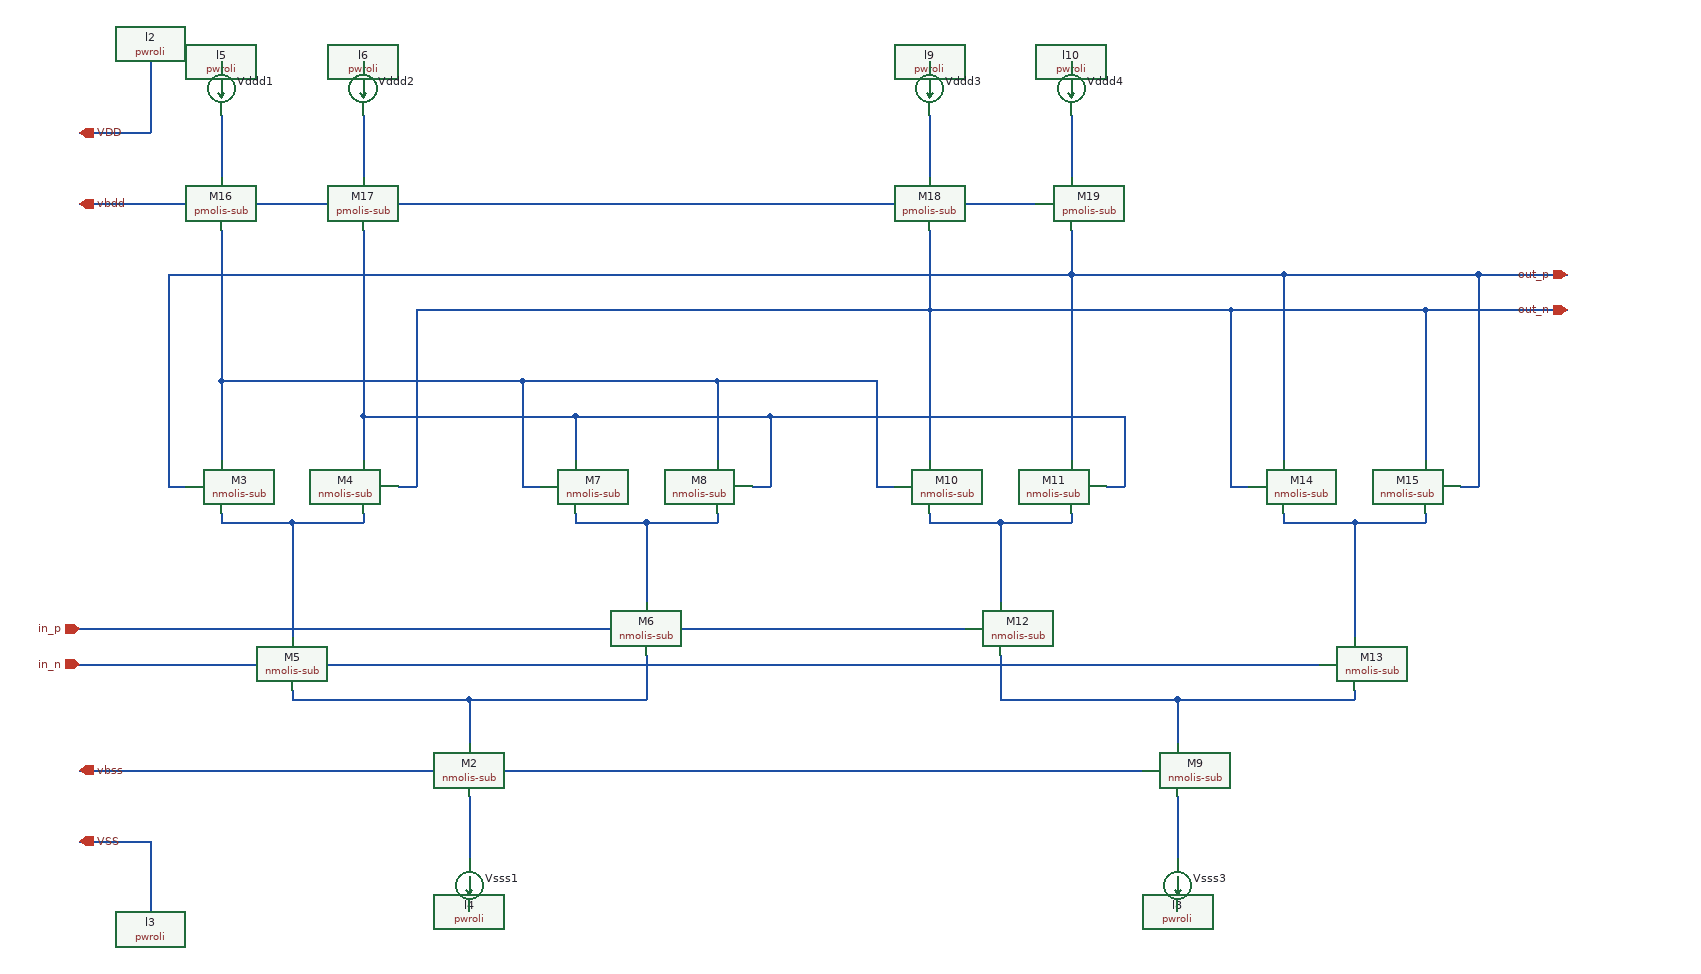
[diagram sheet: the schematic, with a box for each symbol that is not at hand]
v {xschem version=3.4.6 file_version=1.2
*
* This file is part of XSCHEM,
* a schematic capture and Spice/Vhdl/Verilog netlisting tool for circuit
* simulation.
* Copyright (C) 1998-2023 Stefan Frederik Schippers
*
* This program is free software; you can redistribute it and/or modify
* it under the terms of the GNU General Public License as published by
* the Free Software Foundation; either version 2 of the License, or
* (at your option) any later version.
*
* This program is distributed in the hope that it will be useful,
* but WITHOUT ANY WARRANTY; without even the implied warranty of
* MERCHANTABILITY or FITNESS FOR A PARTICULAR PURPOSE.  See the
* GNU General Public License for more details.
*
* You should have received a copy of the GNU General Public License
* along with this program; if not, write to the Free Software
* Foundation, Inc., 51 Franklin Street, Fifth Floor, Boston, MA 02110-1301 USA
}
G {}
K {}
V {}
S {}
E {}
N 1040 -600 1120 -600 {lab=#net1}
N 1040 -600 1040 -510 {lab=#net1}
N 960 -600 1040 -600 {lab=#net1}
N 960 -610 960 -600 {lab=#net1}
N 1120 -610 1120 -600 {lab=#net1}
N 640 -600 720 -600 {lab=#net2}
N 640 -600 640 -470 {lab=#net2}
N 560 -600 640 -600 {lab=#net2}
N 560 -610 560 -600 {lab=#net2}
N 720 -610 720 -600 {lab=#net2}
N 560 -760 560 -670 {lab=#net3}
N 720 -720 720 -670 {lab=#net4}
N 560 -930 560 -760 {lab=#net3}
N 1120 -760 1120 -670 {lab=#net3}
N 720 -720 960 -720 {lab=#net4}
N 720 -930 720 -720 {lab=#net4}
N 960 -720 960 -670 {lab=#net4}
N 900 -640 920 -640 {lab=#net3}
N 900 -760 900 -640 {lab=#net3}
N 560 -760 900 -760 {lab=#net3}
N 960 -720 1180 -720 {lab=#net4}
N 1180 -720 1180 -640 {lab=#net4}
N 1160 -640 1180 -640 {lab=#net4}
N 560 -1060 560 -990 {lab=#net5}
N 720 -1060 720 -990 {lab=#net6}
N 1840 -600 1920 -600 {lab=#net7}
N 1840 -600 1840 -470 {lab=#net7}
N 1760 -600 1840 -600 {lab=#net7}
N 1760 -610 1760 -600 {lab=#net7}
N 1920 -610 1920 -600 {lab=#net7}
N 1440 -600 1520 -600 {lab=#net8}
N 1440 -600 1440 -510 {lab=#net8}
N 1360 -600 1440 -600 {lab=#net8}
N 1360 -610 1360 -600 {lab=#net8}
N 1520 -610 1520 -600 {lab=#net8}
N 1360 -840 1360 -670 {lab=out_n}
N 1520 -880 1520 -670 {lab=out_p}
N 1700 -840 1920 -840 {lab=out_n}
N 1360 -930 1360 -840 {lab=out_n}
N 1920 -840 1920 -670 {lab=out_n}
N 1520 -930 1520 -880 {lab=out_p}
N 1760 -880 1760 -670 {lab=out_p}
N 1700 -640 1720 -640 {lab=out_n}
N 1700 -840 1700 -640 {lab=out_n}
N 1760 -880 1980 -880 {lab=out_p}
N 1980 -880 1980 -640 {lab=out_p}
N 1960 -640 1980 -640 {lab=out_p}
N 1360 -1060 1360 -990 {lab=#net9}
N 1520 -1060 1520 -990 {lab=#net10}
N 1560 -640 1580 -640 {lab=#net4}
N 900 -760 1120 -760 {lab=#net3}
N 500 -640 520 -640 {lab=out_p}
N 760 -640 780 -640 {lab=out_n}
N 1520 -880 1760 -880 {lab=out_p}
N 1180 -720 1580 -720 {lab=#net4}
N 1580 -720 1580 -640 {lab=#net4}
N 1120 -760 1300 -760 {lab=#net3}
N 1300 -760 1300 -640 {lab=#net3}
N 1300 -640 1320 -640 {lab=#net3}
N 500 -880 1520 -880 {lab=out_p}
N 500 -880 500 -640 {lab=out_p}
N 780 -840 780 -640 {lab=out_n}
N 1360 -840 1700 -840 {lab=out_n}
N 780 -840 1360 -840 {lab=out_n}
N 1980 -880 2080 -880 {lab=out_p}
N 1920 -840 2080 -840 {lab=out_n}
N 840 -400 1040 -400 {lab=#net11}
N 840 -400 840 -350 {lab=#net11}
N 640 -400 840 -400 {lab=#net11}
N 1640 -400 1840 -400 {lab=#net12}
N 1640 -400 1640 -350 {lab=#net12}
N 1440 -400 1640 -400 {lab=#net12}
N 840 -290 840 -220 {lab=#net13}
N 1640 -290 1640 -220 {lab=#net14}
N 640 -410 640 -400 {lab=#net11}
N 1040 -450 1040 -400 {lab=#net11}
N 1440 -450 1440 -400 {lab=#net12}
N 1840 -410 1840 -400 {lab=#net12}
N 400 -960 1480 -960 {lab=vbdd}
N 400 -320 1600 -320 {lab=vbss}
N 400 -480 1400 -480 {lab=in_p}
N 400 -440 1800 -440 {lab=in_n}
N 400 -1040 480 -1040 {
lab=VDD}
N 480 -1120 480 -1040 {
lab=VDD}
N 400 -240 480 -240 {
lab=VSS}
N 480 -240 480 -160 {
lab=VSS}
C {title.sym} 160 -30 0 0 {name=l1 author="om"  net_name=true}
C {pwroli.sym} 840 -160 0 0 {name=l4 lab=VSS}
C {ammeter.sym} 840 -190 0 0 {name=Vsss1 
savecurrent=true
lvs_ignore=short}
C {pwroli.sym} 560 -1120 2 0 {name=l5 lab=VDD
}
C {pwroli.sym} 720 -1120 2 0 {name=l6 lab=VDD
}
C {ammeter.sym} 560 -1090 0 0 {name=Vddd1
savecurrent=true
lvs_ignore=short}
C {ammeter.sym} 720 -1090 0 0 {name=Vddd2
savecurrent=true
lvs_ignore=short}
C {pwroli.sym} 1640 -160 0 0 {name=l8 lab=VSS}
C {ammeter.sym} 1640 -190 0 0 {name=Vsss3 
savecurrent=true
lvs_ignore=short}
C {pwroli.sym} 1360 -1120 2 0 {name=l9 lab=VDD
}
C {pwroli.sym} 1520 -1120 2 0 {name=l10 lab=VDD
}
C {ammeter.sym} 1360 -1090 0 0 {name=Vddd3
savecurrent=true
lvs_ignore=short}
C {ammeter.sym} 1520 -1090 0 0 {name=Vddd4
savecurrent=true
lvs_ignore=short}
C {ngspice_probe.sym} 1840 -400 0 0 {name=r7}
C {ngspice_probe.sym} 1040 -400 0 0 {name=r9}
C {ngspice_probe.sym} 680 -600 0 0 {name=r11}
C {ngspice_probe.sym} 1060 -600 0 0 {name=r12}
C {ngspice_probe.sym} 1470 -600 0 0 {name=r14}
C {ngspice_probe.sym} 1870 -600 0 0 {name=r15}
C {ngspice_probe.sym} 1860 -880 0 0 {name=r16}
C {ngspice_probe.sym} 1860 -840 0 0 {name=r17}
C {nmolis-sub.sym} 820 -320 0 0 {name=M2
l=0.13u
w=0.15u
ng=1
m=1
substrate=VSS
model=sg13_lv_nmos
spiceprefix=X
}
C {nmolis-sub.sym} 540 -640 0 0 {name=M3
l=0.13u
w=0.15u
ng=1
m=1
substrate=VSS
model=sg13_lv_nmos
spiceprefix=X
}
C {nmolis-sub.sym} 740 -640 0 1 {name=M4
l=0.13u
w=0.15u
ng=1
m=1
substrate=VSS
model=sg13_lv_nmos
spiceprefix=X
}
C {nmolis-sub.sym} 620 -440 0 0 {name=M5
l=0.13u
w=0.15u
ng=1
m=1
substrate=VSS
model=sg13_lv_nmos
spiceprefix=X
}
C {nmolis-sub.sym} 1020 -480 0 0 {name=M6
l=0.13u
w=0.15u
ng=1
m=1
substrate=VSS
model=sg13_lv_nmos
spiceprefix=X
}
C {nmolis-sub.sym} 940 -640 0 0 {name=M7
l=0.13u
w=0.15u
ng=1
m=1
substrate=VSS
model=sg13_lv_nmos
spiceprefix=X
}
C {nmolis-sub.sym} 1140 -640 0 1 {name=M8
l=0.13u
w=0.15u
ng=1
m=1
substrate=VSS
model=sg13_lv_nmos
spiceprefix=X
}
C {nmolis-sub.sym} 1620 -320 0 0 {name=M9
l=0.13u
w=0.15u
ng=1
m=1
substrate=VSS
model=sg13_lv_nmos
spiceprefix=X
}
C {nmolis-sub.sym} 1340 -640 0 0 {name=M10
l=0.13u
w=0.15u
ng=1
m=1
substrate=VSS
model=sg13_lv_nmos
spiceprefix=X
}
C {nmolis-sub.sym} 1540 -640 0 1 {name=M11
l=0.13u
w=0.15u
ng=1
m=1
substrate=VSS
model=sg13_lv_nmos
spiceprefix=X
}
C {nmolis-sub.sym} 1420 -480 0 0 {name=M12
l=0.13u
w=0.15u
ng=1
m=1
substrate=VSS
model=sg13_lv_nmos
spiceprefix=X
}
C {nmolis-sub.sym} 1820 -440 0 0 {name=M13
l=0.13u
w=0.15u
ng=1
m=1
substrate=VSS
model=sg13_lv_nmos
spiceprefix=X
}
C {nmolis-sub.sym} 1740 -640 0 0 {name=M14
l=0.13u
w=0.15u
ng=1
m=1
substrate=VSS
model=sg13_lv_nmos
spiceprefix=X
}
C {nmolis-sub.sym} 1940 -640 0 1 {name=M15
l=0.13u
w=0.15u
ng=1
m=1
substrate=VSS
model=sg13_lv_nmos
spiceprefix=X
}
C {pmolis-sub.sym} 540 -960 0 0 {name=M16
l=0.13u
w=0.3u
ng=1
m=1
substrate=VDD
model=sg13_lv_pmos
spiceprefix=X
}
C {pmolis-sub.sym} 700 -960 0 0 {name=M17
l=0.13u
w=0.3u
ng=1
m=1
substrate=VDD
model=sg13_lv_pmos
spiceprefix=X
}
C {pmolis-sub.sym} 1340 -960 0 0 {name=M18
l=0.13u
w=0.3u
ng=1
m=1
substrate=VDD
model=sg13_lv_pmos
spiceprefix=X
}
C {pmolis-sub.sym} 1500 -960 0 0 {name=M19
l=0.13u
w=0.3u
ng=1
m=1
substrate=VDD
model=sg13_lv_pmos
spiceprefix=X
}
C {ipin.sym} 400 -480 0 0 {name=p3 lab=in_p
}
C {ipin.sym} 400 -440 0 0 {name=p1 lab=in_n
}
C {opin.sym} 2080 -880 2 1 {name=p5 lab=out_p

}
C {opin.sym} 2080 -840 2 1 {name=p2 lab=out_n

}
C {iopin.sym} 400 -960 0 1 {name=p13 lab=vbdd}
C {iopin.sym} 400 -320 0 1 {name=p4 lab=vbss}
C {iopin.sym} 400 -1040 0 1 {name=p9 lab=VDD}
C {pwroli.sym} 480 -1120 2 0 {name=l2 lab=VDD
}
C {iopin.sym} 400 -240 0 1 {name=p8 lab=VSS

}
C {pwroli.sym} 480 -160 0 0 {name=l3 lab=VSS}
C {launcher.sym} 220 -800 0 0 {name=h1
descr="write LVS netlist"
tclcommand="
	xschem set netlist_type spice
	set lvs_ignore 1
	set lvs_netlist 1
	set spiceprefix 0
	set last_local_netlist_dir $local_netlist_dir
	set local_netlist_dir 0
	xschem netlist [xschem get current_name].cdl
	set local_netlist_dir $last_local_netlist_dir

"
}
C {launcher.sym} 220 -760 0 0 {name=h2
descr="load OP from TOP"
tclcommand="
	xschem annotate_op $\{netlist_dir\}/[file rootname [file tail [xschem get schname 0]]].raw 0;
	xschem load_raw $\{netlist_dir\}/[file rootname [file tail [xschem get schname 0]]]_dc.raw 0;

"
}
